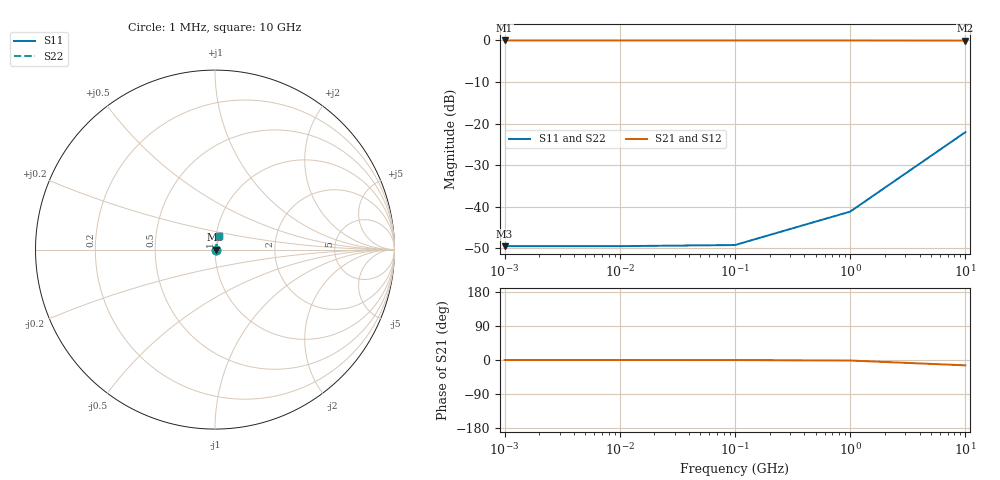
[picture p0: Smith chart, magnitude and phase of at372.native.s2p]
! Sonnet Data File
! From: em Version : 18.53-Lite
! From Project: at372
! Data is NOT De-embedded
! Data File Written: 10/12/2026 12:04:48
!< HDATE 10/12/2026 12:04:48
!< MDATE 10/12/2026 12:04:48
# GHZ S RI R 50.00000
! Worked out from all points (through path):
!   5 points, 1 MHz to 10 GHz, reference 50 ohm
!   highest |S21| = -0.03 dB at 1 MHz (marker M1); lowest = -0.1 dB at 10 GHz (marker M2)
!   lowest |S11| = -49.5 dB at 1 MHz (marker M3), VSWR 1.01, Z = 50.3 + j0.000854 ohm
!   |S11| at or under -10 dB: start of sweep to end of sweep
!   |S22| runs from -49.5 to -22.1 dB; largest |S21 - S12| = 7.4e-13
0.001  0.00335 8.48e-06  0.9966 -2.51e-05  0.9966 -2.51e-05  0.00335 8.48e-06
0.01  0.00335 8.24e-05  0.9966 -0.000249  0.9966 -0.000249  0.00335 8.24e-05
0.1  0.00337 0.000807  0.9966 -0.00247  0.9966 -0.00247  0.00337 0.000807
1  0.0036 0.00795  0.9963 -0.0246  0.9963 -0.0246  0.0036 0.00795
10  0.0227 0.0754  0.9634 -0.2414  0.9634 -0.2414  0.0227 0.0754
